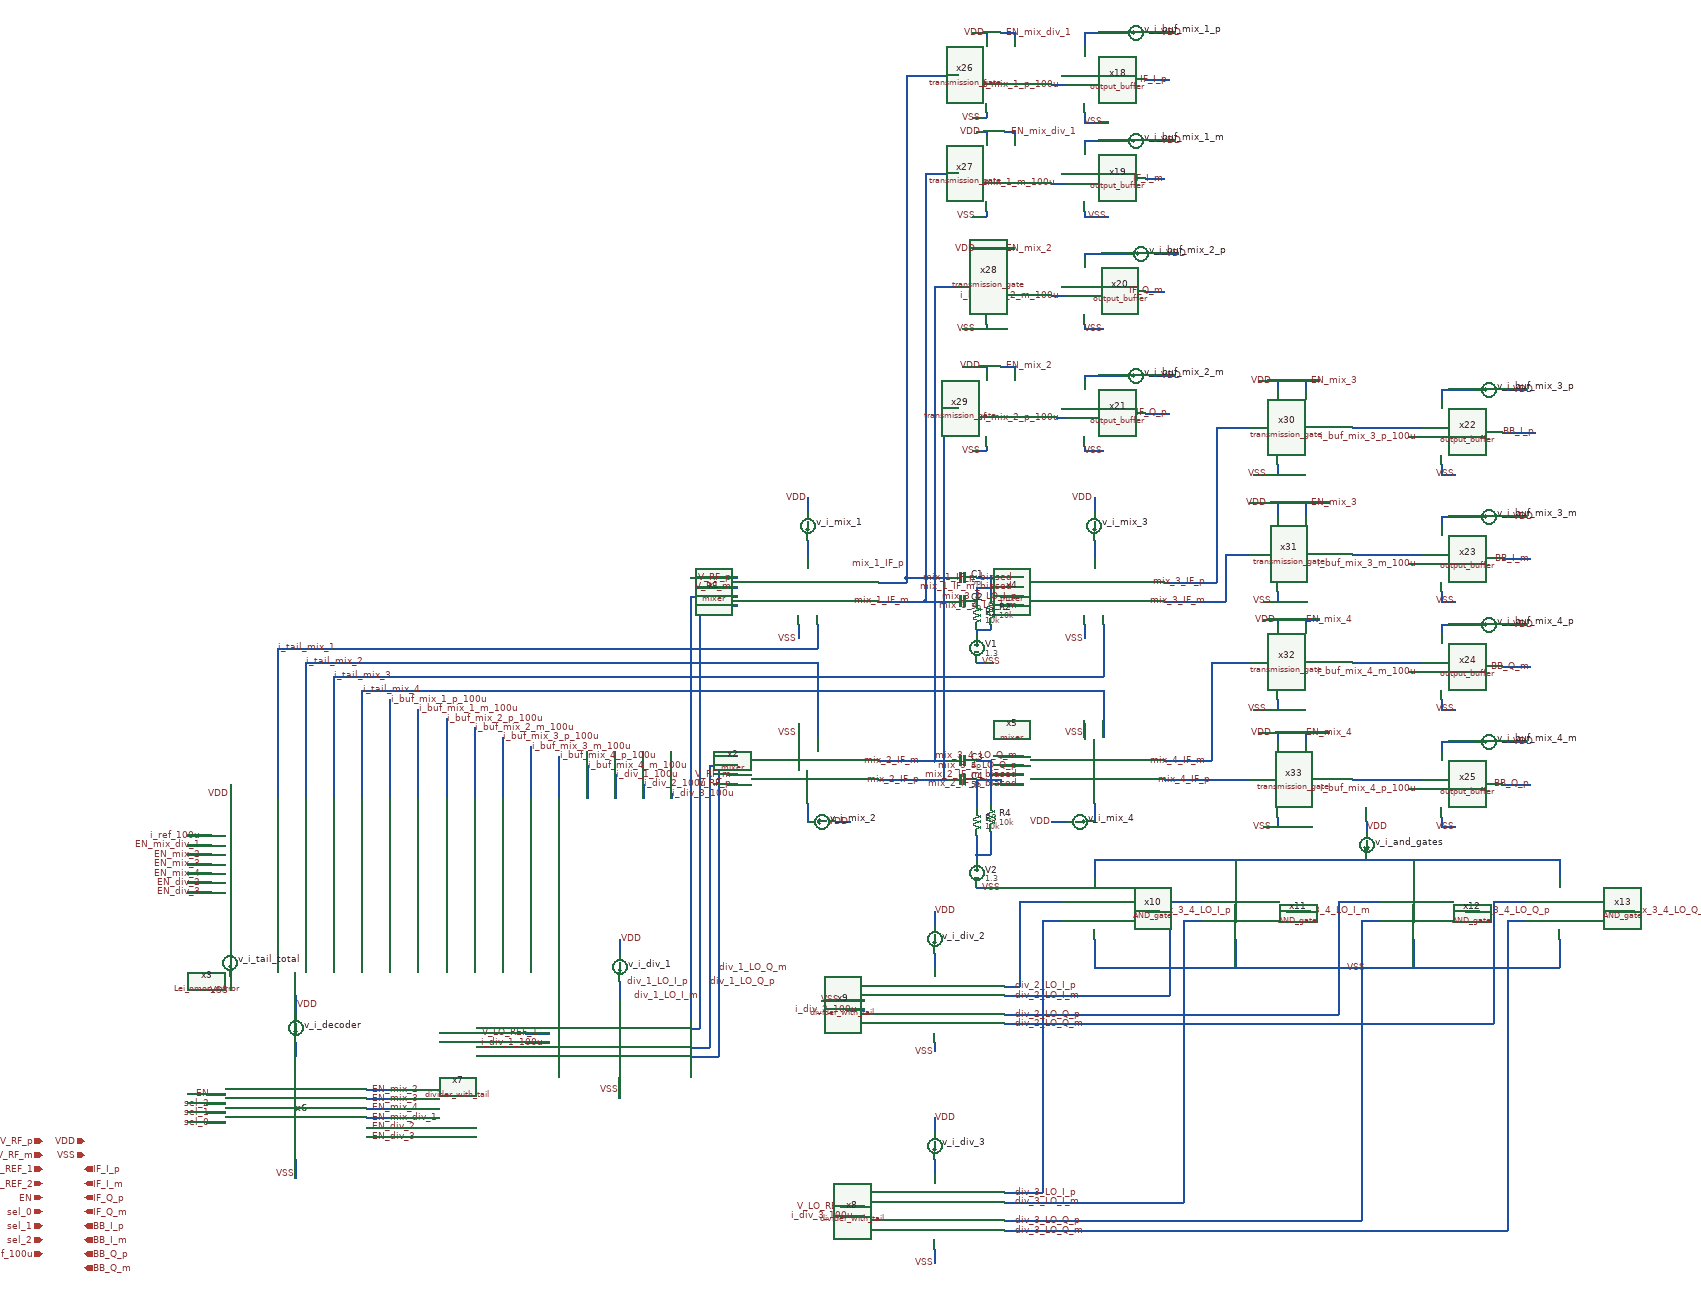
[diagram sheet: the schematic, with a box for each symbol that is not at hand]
v {xschem version=3.4.8RC file_version=1.3}
G {}
K {}
V {}
S {}
F {}
E {}
P 4 1 2100 -1410 {}
N 1630 -1150 1630 -1110 {lab=#net1}
N 1630 -1710 1630 -1670 {lab=#net2}
N 1780 -1620 1840 -1620 {lab=mix_1_IF_p}
N 1780 -1580 1840 -1580 {lab=mix_1_IF_m}
N 1780 -1200 1840 -1200 {lab=mix_2_IF_p}
N 1780 -1240 1840 -1240 {lab=mix_2_IF_m}
N 1610 -1320 1610 -1290 {lab=VSS}
N 2240 -1150 2240 -1110 {lab=#net3}
N 2240 -1710 2240 -1670 {lab=#net4}
N 2390 -1620 2450 -1620 {lab=mix_3_IF_p}
N 2390 -1580 2450 -1580 {lab=mix_3_IF_m}
N 2390 -1200 2450 -1200 {lab=mix_4_IF_p}
N 2390 -1240 2450 -1240 {lab=mix_4_IF_m}
N 2490 -1290 2490 -1240 {lab=mix_4_IF_m}
N 2220 -1320 2220 -1290 {lab=VSS}
N 500 -1480 500 -1350 {lab=i_tail_mix_1}
N 1040 -1480 1650 -1480 {lab=i_tail_mix_1}
N 1650 -1530 1650 -1480 {lab=i_tail_mix_1}
N 560 -1390 560 -1350 {lab=i_tail_mix_2}
N 1100 -1450 1650 -1450 {lab=i_tail_mix_2}
N 560 -1450 560 -1390 {lab=i_tail_mix_2}
N 1650 -1450 1650 -1440 {lab=i_tail_mix_2}
N 620 -1420 620 -1350 {lab=i_tail_mix_3}
N 1160 -1420 2260 -1420 {lab=i_tail_mix_3}
N 2260 -1530 2260 -1420 {lab=i_tail_mix_3}
N 680 -1390 680 -1350 {lab=i_tail_mix_4}
N 1220 -1390 2260 -1390 {lab=i_tail_mix_4}
N 2260 -1390 2260 -1290 {lab=i_tail_mix_4}
N 1610 -1530 1610 -1510 {lab=VSS}
N 1650 -1440 1650 -1290 {lab=i_tail_mix_2}
N 1380 -1440 1380 -690 {lab=div_1_LO_I_p}
N 1380 -1590 1480 -1590 {lab=div_1_LO_I_p}
N 1380 -670 1400 -670 {lab=div_1_LO_I_m}
N 1400 -1570 1480 -1570 {lab=div_1_LO_I_m}
N 1030 -640 1080 -640 {lab=i_div_1_100u}
N 1030 -660 1080 -660 {lab=V_LO_REF_1}
N 1700 -270 1750 -270 {lab=i_div_3_100u}
N 1700 -290 1750 -290 {lab=V_LO_REF_2}
N 1710 -710 1750 -710 {lab=i_div_2_100u}
N 1710 -730 1750 -730 {lab=VSS}
N 1900 -830 1900 -800 {lab=#net5}
N 1900 -640 1900 -620 {lab=VSS}
N 1900 -390 1900 -360 {lab=#net6}
N 1900 -200 1900 -170 {lab=VSS}
N 1380 -630 1420 -630 {lab=div_1_LO_Q_p}
N 1420 -1100 1420 -630 {lab=div_1_LO_Q_p}
N 1380 -610 1440 -610 {lab=div_1_LO_Q_m}
N 1440 -1080 1440 -610 {lab=div_1_LO_Q_m}
N 2050 -760 2070 -760 {lab=div_2_LO_I_p}
N 2050 -740 2080 -740 {lab=div_2_LO_I_m}
N 1660 -730 1710 -730 {lab=VSS}
N 2400 -920 2400 -740 {lab=div_2_LO_I_m}
N 2350 -920 2380 -920 {lab=mix_3_4_LO_I_p}
N 2650 -920 2700 -920 {lab=mix_3_4_LO_I_m}
N 2760 -920 2760 -760 {lab=div_2_LO_Q_p}
N 3090 -920 3090 -740 {lab=div_2_LO_Q_m}
N 3030 -920 3060 -920 {lab=mix_3_4_LO_Q_p}
N 3340 -920 3390 -920 {lab=mix_3_4_LO_Q_m}
N 2050 -700 2760 -700 {lab=div_2_LO_Q_p}
N 2760 -760 2760 -700 {lab=div_2_LO_Q_p}
N 3090 -740 3090 -690 {lab=div_2_LO_Q_m}
N 2240 -1030 2240 -1010 {lab=#net7}
N 3230 -1030 3230 -1010 {lab=#net7}
N 2540 -1030 2540 -990 {lab=#net7}
N 2920 -1030 2920 -990 {lab=#net7}
N 2240 -830 2240 -800 {lab=VSS}
N 3230 -820 3230 -800 {lab=VSS}
N 3230 -830 3230 -820 {lab=VSS}
N 2920 -830 2920 -800 {lab=VSS}
N 2540 -830 2540 -800 {lab=VSS}
N 2810 -900 2850 -900 {lab=div_3_LO_Q_p}
N 2050 -680 3090 -680 {lab=div_2_LO_Q_m}
N 3090 -690 3090 -680 {lab=div_2_LO_Q_m}
N 3120 -900 3160 -900 {lab=div_3_LO_Q_m}
N 2080 -740 2400 -740 {lab=div_2_LO_I_m}
N 2430 -900 2470 -900 {lab=div_3_LO_I_m}
N 2130 -900 2170 -900 {lab=div_3_LO_I_p}
N 1230 -770 1230 -730 {lab=#net8}
N 1230 -570 1230 -520 {lab=VSS}
N 690 -540 740 -540 {lab=EN_mix_2}
N 690 -520 740 -520 {lab=EN_mix_3}
N 690 -500 740 -500 {lab=EN_mix_4}
N 690 -480 740 -480 {lab=EN_mix_div_1}
N 690 -460 740 -460 {lab=EN_div_2}
N 690 -440 740 -440 {lab=EN_div_3}
N 350 -530 390 -530 {lab=EN}
N 350 -510 390 -510 {lab=sel_2}
N 350 -490 390 -490 {lab=sel_1}
N 350 -470 390 -470 {lab=sel_0}
N 540 -640 540 -610 {lab=#net9}
N 540 -390 540 -350 {lab=VSS}
N 1380 -1630 1480 -1630 {lab=V_RF_p}
N 1390 -1610 1480 -1610 {lab=V_RF_m}
N 1460 -1210 1480 -1210 {lab=V_RF_m}
N 1460 -1190 1480 -1190 {lab=V_RF_p}
N 2050 -320 2070 -320 {lab=div_3_LO_I_p}
N 2050 -300 2080 -300 {lab=div_3_LO_I_m}
N 1840 -1630 1840 -1620 {lab=mix_1_IF_p}
N 1840 -1580 1860 -1580 {lab=mix_1_IF_m}
N 1860 -1580 1880 -1580 {lab=mix_1_IF_m}
N 1880 -1690 1880 -1580 {lab=mix_1_IF_m}
N 2040 -1590 2090 -1590 {lab=mix_3_4_LO_I_p}
N 2040 -1570 2090 -1570 {lab=mix_3_4_LO_I_m}
N 1840 -1790 1840 -1630 {lab=mix_1_IF_p}
N 2220 -1530 2220 -1500 {lab=VSS}
N 1610 -1510 1610 -1500 {lab=VSS}
N 1840 -1240 1900 -1240 {lab=mix_2_IF_m}
N 1840 -1200 1920 -1200 {lab=mix_2_IF_p}
N 1920 -1230 1920 -1200 {lab=mix_2_IF_p}
N 1920 -1770 1920 -1230 {lab=mix_2_IF_p}
N 1880 -1870 1880 -1690 {lab=mix_1_IF_m}
N 1840 -2550 1840 -1790 {lab=mix_1_IF_p}
N 1840 -2700 1950 -2700 {lab=mix_1_IF_p}
N 1880 -2360 1880 -1870 {lab=mix_1_IF_m}
N 1880 -2490 1950 -2490 {lab=mix_1_IF_m}
N 1900 -2180 1900 -1810 {lab=mix_2_IF_m}
N 1900 -2250 1950 -2250 {lab=mix_2_IF_m}
N 1920 -1990 1920 -1770 {lab=mix_2_IF_p}
N 1920 -1990 1950 -1990 {lab=mix_2_IF_p}
N 2350 -2690 2400 -2690 {lab=IF_I_p}
N 2220 -2790 2220 -2760 {lab=#net10}
N 2220 -2790 2260 -2790 {lab=#net10}
N 2220 -2620 2220 -2600 {lab=VSS}
N 2220 -2600 2270 -2600 {lab=VSS}
N 2220 -2560 2220 -2550 {lab=#net11}
N 2220 -2560 2260 -2560 {lab=#net11}
N 2220 -2410 2220 -2400 {lab=VSS}
N 2220 -2400 2270 -2400 {lab=VSS}
N 2220 -2320 2220 -2310 {lab=#net12}
N 2220 -2320 2270 -2320 {lab=#net12}
N 2220 -2170 2220 -2160 {lab=VSS}
N 2220 -2160 2260 -2160 {lab=VSS}
N 2220 -2060 2220 -2050 {lab=#net13}
N 2220 -2060 2260 -2060 {lab=#net13}
N 2220 -1910 2220 -1900 {lab=VSS}
N 2220 -1900 2260 -1900 {lab=VSS}
N 2350 -1980 2400 -1980 {lab=IF_Q_p}
N 2350 -2240 2390 -2240 {lab=IF_Q_m}
N 2350 -2480 2390 -2480 {lab=IF_I_m}
N 2150 -2470 2180 -2470 {lab=i_buf_mix_1_m_100u}
N 2150 -2680 2180 -2680 {lab=i_buf_mix_1_p_100u}
N 2150 -2230 2180 -2230 {lab=i_buf_mix_2_m_100u}
N 2160 -1970 2180 -1970 {lab=i_buf_mix_2_p_100u}
N 2810 -1200 2930 -1200 {lab=#net14}
N 2930 -1200 2940 -1200 {lab=#net14}
N 2450 -1240 2490 -1240 {lab=mix_4_IF_m}
N 2490 -1390 2490 -1290 {lab=mix_4_IF_m}
N 2850 -1450 2940 -1450 {lab=#net15}
N 2810 -1680 2940 -1680 {lab=#net16}
N 2450 -1620 2500 -1620 {lab=mix_3_IF_p}
N 2500 -1770 2500 -1620 {lab=mix_3_IF_p}
N 2860 -1950 2940 -1950 {lab=#net17}
N 2980 -2030 2980 -2010 {lab=#net18}
N 2980 -2030 3010 -2030 {lab=#net18}
N 2980 -1870 2980 -1850 {lab=VSS}
N 2980 -1850 3010 -1850 {lab=VSS}
N 2980 -1760 2980 -1740 {lab=#net19}
N 2980 -1760 3010 -1760 {lab=#net19}
N 2980 -1600 2980 -1580 {lab=VSS}
N 2980 -1580 3010 -1580 {lab=VSS}
N 2980 -1530 2980 -1510 {lab=#net20}
N 2980 -1530 3010 -1530 {lab=#net20}
N 2980 -1370 2980 -1350 {lab=VSS}
N 2980 -1350 3010 -1350 {lab=VSS}
N 2980 -1280 2980 -1260 {lab=#net21}
N 2980 -1280 3010 -1280 {lab=#net21}
N 2980 -1120 2980 -1100 {lab=VSS}
N 2980 -1100 3010 -1100 {lab=VSS}
N 2910 -1930 2940 -1930 {lab=i_buf_mix_3_p_100u}
N 2910 -1660 2940 -1660 {lab=i_buf_mix_3_m_100u}
N 2910 -1430 2940 -1430 {lab=i_buf_mix_4_m_100u}
N 2910 -1180 2940 -1180 {lab=i_buf_mix_4_p_100u}
N 3110 -1940 3180 -1940 {lab=BB_I_p}
N 3110 -1670 3170 -1670 {lab=BB_I_m}
N 3110 -1440 3170 -1440 {lab=BB_Q_m}
N 3110 -1190 3170 -1190 {lab=BB_Q_p}
N 640 -1480 1040 -1480 {lab=i_tail_mix_1}
N 700 -1450 1100 -1450 {lab=i_tail_mix_2}
N 760 -1420 1160 -1420 {lab=i_tail_mix_3}
N 820 -1390 1220 -1390 {lab=i_tail_mix_4}
N 2040 -1250 2090 -1250 {lab=mix_3_4_LO_Q_m}
N 2040 -1230 2090 -1230 {lab=mix_3_4_LO_Q_p}
N 2040 -1210 2090 -1210 {lab=mix_2_IF_m_biased}
N 2040 -1190 2090 -1190 {lab=mix_2_IF_p_biased}
N 500 -1350 500 -1240 {lab=i_tail_mix_1}
N 560 -1350 560 -1240 {lab=i_tail_mix_2}
N 620 -1340 620 -1240 {lab=i_tail_mix_3}
N 620 -1350 620 -1340 {lab=i_tail_mix_3}
N 680 -1350 680 -1240 {lab=i_tail_mix_4}
N 740 -1370 740 -1240 {lab=i_buf_mix_1_p_100u}
N 800 -1350 800 -1240 {lab=i_buf_mix_1_m_100u}
N 860 -1330 860 -1240 {lab=i_buf_mix_2_p_100u}
N 920 -1300 920 -1240 {lab=i_buf_mix_2_m_100u}
N 920 -1310 920 -1300 {lab=i_buf_mix_2_m_100u}
N 500 -1480 640 -1480 {lab=i_tail_mix_1}
N 560 -1450 700 -1450 {lab=i_tail_mix_2}
N 620 -1420 760 -1420 {lab=i_tail_mix_3}
N 680 -1390 820 -1390 {lab=i_tail_mix_4}
N 500 -1240 500 -1230 {lab=i_tail_mix_1}
N 560 -1240 560 -1230 {lab=i_tail_mix_2}
N 620 -1240 620 -1230 {lab=i_tail_mix_3}
N 680 -1240 680 -1230 {lab=i_tail_mix_4}
N 740 -1240 740 -1230 {lab=i_buf_mix_1_p_100u}
N 800 -1240 800 -1230 {lab=i_buf_mix_1_m_100u}
N 860 -1240 860 -1230 {lab=i_buf_mix_2_p_100u}
N 920 -1240 920 -1230 {lab=i_buf_mix_2_m_100u}
N 980 -1240 980 -1230 {lab=i_buf_mix_3_p_100u}
N 1040 -1240 1040 -1230 {lab=i_buf_mix_3_m_100u}
N 980 -1290 980 -1240 {lab=i_buf_mix_3_p_100u}
N 1040 -1270 1040 -1240 {lab=i_buf_mix_3_m_100u}
N 1100 -1250 1100 -1230 {lab=i_buf_mix_4_p_100u}
N 1900 -1810 1900 -1240 {lab=mix_2_IF_m}
N 310 -1080 360 -1080 {lab=i_ref_100u}
N 310 -1060 360 -1060 {lab=EN_mix_div_1}
N 310 -1040 360 -1040 {lab=EN_mix_2}
N 310 -1020 360 -1020 {lab=EN_mix_3}
N 310 -1000 360 -1000 {lab=EN_mix_4}
N 400 -1190 400 -1160 {lab=VDD}
N 400 -870 400 -840 {lab=#net22}
N 1630 -1800 1630 -1770 {lab=VDD}
N 2240 -1800 2240 -1770 {lab=VDD}
N 2150 -1110 2180 -1110 {lab=VDD}
N 1690 -1110 1720 -1110 {lab=VDD}
N 1230 -860 1230 -830 {lab=VDD}
N 1900 -920 1900 -890 {lab=VDD}
N 1900 -480 1900 -450 {lab=VDD}
N 400 -780 400 -750 {lab=VSS}
N 2360 -2790 2410 -2790 {lab=VDD}
N 2260 -2790 2300 -2790 {lab=#net10}
N 2360 -2560 2410 -2560 {lab=VDD}
N 2260 -2560 2300 -2560 {lab=#net11}
N 2370 -2320 2420 -2320 {lab=VDD}
N 2270 -2320 2310 -2320 {lab=#net12}
N 2360 -2060 2410 -2060 {lab=VDD}
N 2260 -2060 2300 -2060 {lab=#net13}
N 3110 -2030 3160 -2030 {lab=VDD}
N 3010 -2030 3050 -2030 {lab=#net18}
N 3110 -1760 3160 -1760 {lab=VDD}
N 3010 -1760 3050 -1760 {lab=#net19}
N 3110 -1530 3160 -1530 {lab=VDD}
N 3010 -1530 3050 -1530 {lab=#net20}
N 3110 -1280 3160 -1280 {lab=VDD}
N 3010 -1280 3050 -1280 {lab=#net21}
N 540 -740 540 -700 {lab=VDD}
N 2820 -1110 2820 -1090 {lab=VDD}
N 2170 -1990 2180 -1990 {lab=#net23}
N 2170 -2250 2180 -2250 {lab=#net24}
N 2170 -2490 2180 -2490 {lab=#net25}
N 2170 -2700 2180 -2700 {lab=#net26}
N 2010 -2170 2010 -2160 {lab=VSS}
N 1960 -2160 2010 -2160 {lab=VSS}
N 2010 -2080 2010 -2070 {lab=VDD}
N 1960 -2080 2010 -2080 {lab=VDD}
N 2010 -1910 2010 -1900 {lab=VSS}
N 1980 -1900 2010 -1900 {lab=VSS}
N 1980 -2330 2010 -2330 {lab=VDD}
N 1840 -2700 1840 -2550 {lab=mix_1_IF_p}
N 2010 -2620 2010 -2610 {lab=VSS}
N 1980 -2610 2010 -2610 {lab=VSS}
N 2010 -2790 2010 -2780 {lab=VDD}
N 1980 -2790 2010 -2790 {lab=VDD}
N 2070 -2790 2070 -2780 {lab=EN_mix_div_1}
N 2040 -2790 2070 -2790 {lab=EN_mix_div_1}
N 1880 -2490 1880 -2360 {lab=mix_1_IF_m}
N 2010 -2410 2010 -2400 {lab=VSS}
N 1980 -2400 2010 -2400 {lab=VSS}
N 2010 -2580 2010 -2570 {lab=VDD}
N 1990 -2580 2010 -2580 {lab=VDD}
N 2070 -2580 2070 -2570 {lab=EN_mix_div_1}
N 2050 -2580 2070 -2580 {lab=EN_mix_div_1}
N 1900 -2240 1900 -2180 {lab=mix_2_IF_m}
N 1900 -2250 1900 -2240 {lab=mix_2_IF_m}
N 2070 -2080 2070 -2070 {lab=EN_mix_2}
N 2040 -2080 2070 -2080 {lab=EN_mix_2}
N 2050 -2330 2070 -2330 {lab=EN_mix_2}
N 2450 -1200 2570 -1200 {lab=mix_4_IF_p}
N 2790 -1200 2810 -1200 {lab=#net14}
N 2630 -1300 2630 -1280 {lab=VDD}
N 2590 -1300 2630 -1300 {lab=VDD}
N 2630 -1120 2630 -1100 {lab=VSS}
N 2600 -1100 2630 -1100 {lab=VSS}
N 2490 -1450 2490 -1390 {lab=mix_4_IF_m}
N 2490 -1450 2570 -1450 {lab=mix_4_IF_m}
N 2630 -1370 2630 -1350 {lab=VSS}
N 2580 -1350 2630 -1350 {lab=VSS}
N 2630 -1540 2630 -1530 {lab=VDD}
N 2600 -1540 2630 -1540 {lab=VDD}
N 2690 -1540 2690 -1530 {lab=EN_mix_4}
N 2690 -1540 2720 -1540 {lab=EN_mix_4}
N 2790 -1450 2850 -1450 {lab=#net15}
N 2450 -1580 2520 -1580 {lab=mix_3_IF_m}
N 2500 -1950 2500 -1770 {lab=mix_3_IF_p}
N 2500 -1950 2560 -1950 {lab=mix_3_IF_p}
N 2560 -1950 2570 -1950 {lab=mix_3_IF_p}
N 2520 -1680 2520 -1580 {lab=mix_3_IF_m}
N 2520 -1680 2570 -1680 {lab=mix_3_IF_m}
N 2630 -1790 2630 -1760 {lab=VDD}
N 2570 -1790 2630 -1790 {lab=VDD}
N 2690 -1790 2690 -1760 {lab=EN_mix_3}
N 2690 -1790 2740 -1790 {lab=EN_mix_3}
N 2630 -1600 2630 -1580 {lab=VSS}
N 2600 -1580 2630 -1580 {lab=VSS}
N 2630 -1870 2630 -1850 {lab=VSS}
N 2580 -1850 2630 -1850 {lab=VSS}
N 2630 -2050 2630 -2030 {lab=VDD}
N 2590 -2050 2630 -2050 {lab=VDD}
N 2690 -2050 2690 -2030 {lab=EN_mix_3}
N 2690 -2050 2720 -2050 {lab=EN_mix_3}
N 2790 -1950 2860 -1950 {lab=#net17}
N 2690 -1300 2690 -1280 {lab=EN_mix_4}
N 2690 -1300 2740 -1300 {lab=EN_mix_4}
N 2790 -1680 2810 -1680 {lab=#net16}
N 1840 -1630 1930 -1630 {lab=mix_1_IF_p}
N 1880 -1580 1930 -1580 {lab=mix_1_IF_m}
N 1990 -1610 1990 -1580 {lab=mix_1_IF_m_biased}
N 1990 -1520 1990 -1510 {lab=#net27}
N 1990 -1520 2020 -1520 {lab=#net27}
N 1990 -1040 1990 -1030 {lab=#net28}
N 1990 -1040 2020 -1040 {lab=#net28}
N 2020 -1070 2020 -1040 {lab=#net28}
N 1920 -1200 1930 -1200 {lab=mix_2_IF_p}
N 1900 -1240 1930 -1240 {lab=mix_2_IF_m}
N 1990 -1240 2020 -1240 {lab=mix_2_IF_m_biased}
N 2020 -1240 2020 -1210 {lab=mix_2_IF_m_biased}
N 1990 -1200 1990 -1190 {lab=mix_2_IF_p_biased}
N 1990 -1450 2010 -1450 {lab=VSS}
N 1990 -970 2010 -970 {lab=VSS}
N 2020 -1530 2020 -1520 {lab=#net27}
N 1990 -1080 1990 -1040 {lab=#net28}
N 2020 -1090 2020 -1070 {lab=#net28}
N 2020 -1210 2020 -1150 {lab=mix_2_IF_m_biased}
N 1990 -1190 1990 -1140 {lab=mix_2_IF_p_biased}
N 1380 -1590 1380 -1440 {lab=div_1_LO_I_p
}
N 310 -980 360 -980 {lab=EN_div_2}
N 310 -960 360 -960 {lab=EN_div_3}
N 500 -1230 500 -1160 {lab=i_tail_mix_1}
N 560 -1230 560 -1160 {lab=i_tail_mix_2}
N 620 -1230 620 -1160 {lab=i_tail_mix_3}
N 680 -1230 680 -1160 {lab=i_tail_mix_4}
N 740 -1230 740 -1170 {lab=i_buf_mix_1_p_100u}
N 740 -1170 740 -1160 {lab=i_buf_mix_1_p_100u}
N 800 -1230 800 -1160 {lab=i_buf_mix_1_m_100u}
N 860 -1230 860 -1160 {lab=i_buf_mix_2_p_100u}
N 920 -1230 920 -1160 {lab=i_buf_mix_2_m_100u}
N 980 -1230 980 -1160 {lab=i_buf_mix_3_p_100u}
N 1040 -1230 1040 -1160 {lab=i_buf_mix_3_m_100u}
N 1100 -1230 1100 -1160 {lab=i_buf_mix_4_p_100u}
N 1160 -1230 1160 -1160 {lab=i_buf_mix_4_m_100u}
N 1220 -1210 1220 -1160 {lab=i_div_1_100u}
N 1280 -1190 1280 -1160 {lab=i_div_2_100u}
N 1340 -1170 1340 -1160 {lab=i_div_3_100u}
N 1440 -1250 1480 -1250 {lab=div_1_LO_Q_m}
N 1420 -1230 1420 -1100 {lab=div_1_LO_Q_p
spice_ignore=short}
N 1420 -1230 1480 -1230 {lab=div_1_LO_Q_p}
N 1440 -1250 1440 -1080 {lab=div_1_LO_Q_m
spice_ignore=short}
N 1990 -1630 2020 -1630 {lab=mix_1_IF_p_biased}
N 1990 -1610 2010 -1610 {lab=mix_1_IF_m_biased}
N 2020 -1620 2020 -1590 {lab=mix_1_IF_p_biased}
N 2020 -1630 2020 -1620 {lab=mix_1_IF_p_biased}
N 2010 -1610 2090 -1610 {lab=mix_1_IF_m_biased}
N 2020 -1630 2090 -1630 {lab=mix_1_IF_p_biased}
N 2040 -1200 2040 -1190 {lab=mix_2_IF_p_biased}
N 1990 -1200 2040 -1200 {lab=mix_2_IF_p_biased}
N 2020 -1210 2040 -1210 {lab=mix_2_IF_m_biased}
N 1400 -1350 1400 -670 {lab=div_1_LO_I_m}
N 1400 -1570 1400 -1350 {lab=div_1_LO_I_m
}
N 2240 -1010 2240 -990 {lab=#net7}
N 2240 -850 2240 -830 {lab=VSS}
N 2240 -860 2240 -850 {lab=VSS}
N 2540 -860 2540 -830 {lab=VSS}
N 2920 -850 2920 -830 {lab=VSS}
N 2920 -860 2920 -850 {lab=VSS}
N 2240 -1030 3230 -1030 {lab=#net7}
N 2240 -800 3230 -800 {lab=VSS}
N 2140 -940 2170 -940 {lab=div_2_LO_I_p}
N 2400 -940 2400 -920 {lab=div_2_LO_I_m}
N 2400 -940 2470 -940 {lab=div_2_LO_I_m}
N 3090 -940 3090 -920 {lab=div_2_LO_Q_m}
N 3090 -940 3160 -940 {lab=div_2_LO_Q_m}
N 2760 -940 2760 -920 {lab=div_2_LO_Q_p}
N 2760 -940 2850 -940 {lab=div_2_LO_Q_p}
N 3230 -860 3230 -830 {lab=VSS}
N 3230 -1010 3230 -990 {lab=#net7}
N 2080 -300 2220 -300 {lab=div_3_LO_I_m}
N 2050 -260 2220 -260 {lab=div_3_LO_Q_p}
N 2050 -240 2220 -240 {lab=div_3_LO_Q_m}
N 2070 -760 2080 -760 {lab=div_2_LO_I_p}
N 2080 -940 2080 -760 {lab=div_2_LO_I_p}
N 2080 -940 2140 -940 {lab=div_2_LO_I_p}
N 2130 -900 2130 -320 {lab=div_3_LO_I_p}
N 2070 -320 2130 -320 {lab=div_3_LO_I_p}
N 2430 -900 2430 -300 {lab=div_3_LO_I_m}
N 2230 -300 2430 -300 {lab=div_3_LO_I_m}
N 2220 -300 2230 -300 {lab=div_3_LO_I_m}
N 2220 -260 2760 -260 {lab=div_3_LO_Q_p}
N 2810 -900 2810 -260 {lab=div_3_LO_Q_p}
N 2760 -260 2810 -260 {lab=div_3_LO_Q_p}
N 3120 -900 3120 -240 {lab=div_3_LO_Q_m}
N 2220 -240 3120 -240 {lab=div_3_LO_Q_m}
C {title.sym} 160 -30 0 0 {name=l1 author="Lei Chen"}
C {mixer/schematic/mixer.sym} 1630 -1600 0 0 {name=x1
}
C {mixer/schematic/mixer.sym} 1630 -1220 2 1 {name=x2
}
C {mixer/schematic/mixer.sym} 2240 -1600 0 0 {name=x4
}
C {mixer/schematic/mixer.sym} 2240 -1220 2 1 {name=x5
}
C {decoder/schematic/decoder.sym} 540 -500 0 0 {name=x6}
C {iopin.sym} 90 -430 0 0 {name=p1 lab=VDD}
C {iopin.sym} 90 -400 0 0 {name=p2 lab=VSS}
C {lab_wire.sym} 2820 -1100 0 1 {name=p3 sig_type=std_logic lab=VDD}
C {lab_wire.sym} 2820 -800 0 0 {name=p4 sig_type=std_logic lab=VSS}
C {lab_wire.sym} 1900 -620 0 0 {name=p6 sig_type=std_logic lab=VSS}
C {lab_wire.sym} 1900 -170 0 0 {name=p8 sig_type=std_logic lab=VSS}
C {ipin.sym} 0 -430 0 0 {name=p9 lab=V_RF_p}
C {ipin.sym} 0 -400 0 0 {name=p10 lab=V_RF_m}
C {ipin.sym} 0 -370 0 0 {name=p11 lab=V_LO_REF_1}
C {ipin.sym} 0 -340 0 0 {name=p12 lab=V_LO_REF_2}
C {ipin.sym} 0 -310 0 0 {name=p13 lab=EN}
C {ipin.sym} 0 -280 0 0 {name=p14 lab=sel_0}
C {ipin.sym} 0 -250 0 0 {name=p15 lab=sel_1}
C {ipin.sym} 0 -220 0 0 {name=p16 lab=sel_2}
C {lab_wire.sym} 360 -530 0 0 {name=p17 sig_type=std_logic lab=EN}
C {lab_wire.sym} 360 -510 0 0 {name=p18 sig_type=std_logic lab=sel_2}
C {lab_wire.sym} 360 -490 0 0 {name=p19 sig_type=std_logic lab=sel_1}
C {lab_wire.sym} 360 -470 0 0 {name=p20 sig_type=std_logic lab=sel_0}
C {lab_wire.sym} 700 -540 0 1 {name=p21 sig_type=std_logic lab=EN_mix_2}
C {lab_wire.sym} 700 -520 0 1 {name=p22 sig_type=std_logic lab=EN_mix_3}
C {lab_wire.sym} 700 -500 0 1 {name=p23 sig_type=std_logic lab=EN_mix_4}
C {lab_wire.sym} 700 -480 0 1 {name=p24 sig_type=std_logic lab=EN_mix_div_1}
C {lab_wire.sym} 700 -460 0 1 {name=p25 sig_type=std_logic lab=EN_div_2}
C {lab_wire.sym} 700 -440 0 1 {name=p26 sig_type=std_logic lab=EN_div_3}
C {lab_wire.sym} 340 -1020 0 0 {name=p27 sig_type=std_logic lab=EN_mix_3}
C {lab_wire.sym} 340 -1040 0 0 {name=p28 sig_type=std_logic lab=EN_mix_2}
C {lab_wire.sym} 340 -1000 0 0 {name=p29 sig_type=std_logic lab=EN_mix_4}
C {lab_wire.sym} 340 -1060 0 0 {name=p30 sig_type=std_logic lab=EN_mix_div_1}
C {ipin.sym} 0 -190 0 0 {name=p31 lab=i_ref_100u}
C {lab_wire.sym} 340 -1080 0 0 {name=p32 sig_type=std_logic lab=i_ref_100u}
C {lab_wire.sym} 540 -720 0 1 {name=p36 sig_type=std_logic lab=VDD}
C {lab_wire.sym} 1230 -540 0 0 {name=p37 sig_type=std_logic lab=VSS}
C {lab_wire.sym} 540 -360 0 0 {name=p38 sig_type=std_logic lab=VSS}
C {lab_wire.sym} 500 -1480 0 1 {name=p39 sig_type=std_logic lab=i_tail_mix_1}
C {lab_wire.sym} 560 -1450 0 1 {name=p40 sig_type=std_logic lab=i_tail_mix_2}
C {lab_wire.sym} 620 -1420 0 1 {name=p41 sig_type=std_logic lab=i_tail_mix_3}
C {lab_wire.sym} 680 -1390 0 1 {name=p42 sig_type=std_logic lab=i_tail_mix_4}
C {lab_wire.sym} 1470 -1630 0 0 {name=p43 sig_type=std_logic lab=V_RF_p}
C {lab_wire.sym} 1470 -1610 0 0 {name=p44 sig_type=std_logic lab=V_RF_m}
C {lab_wire.sym} 1470 -1190 0 0 {name=p45 sig_type=std_logic lab=V_RF_p}
C {lab_wire.sym} 1470 -1210 0 0 {name=p46 sig_type=std_logic lab=V_RF_m}
C {lab_wire.sym} 1380 -770 0 0 {name=p47 sig_type=std_logic lab=div_1_LO_I_p}
C {lab_wire.sym} 1400 -740 0 0 {name=p48 sig_type=std_logic lab=div_1_LO_I_m}
C {lab_wire.sym} 1440 -800 0 1 {name=p49 sig_type=std_logic lab=div_1_LO_Q_m}
C {lab_wire.sym} 1420 -770 0 1 {name=p50 sig_type=std_logic lab=div_1_LO_Q_p}
C {lab_wire.sym} 1060 -660 0 0 {name=p51 sig_type=std_logic lab=V_LO_REF_1}
C {lab_wire.sym} 1730 -290 0 0 {name=p55 sig_type=std_logic lab=V_LO_REF_2}
C {lab_wire.sym} 2070 -760 0 1 {name=p56 sig_type=std_logic lab=div_2_LO_I_p}
C {lab_wire.sym} 2070 -740 0 1 {name=p57 sig_type=std_logic lab=div_2_LO_I_m}
C {lab_wire.sym} 2070 -700 0 1 {name=p58 sig_type=std_logic lab=div_2_LO_Q_p}
C {lab_wire.sym} 2070 -680 0 1 {name=p59 sig_type=std_logic lab=div_2_LO_Q_m}
C {lab_wire.sym} 2070 -320 0 1 {name=p62 sig_type=std_logic lab=div_3_LO_I_p}
C {lab_wire.sym} 2070 -300 0 1 {name=p63 sig_type=std_logic lab=div_3_LO_I_m}
C {lab_wire.sym} 2070 -260 0 1 {name=p64 sig_type=std_logic lab=div_3_LO_Q_p}
C {lab_wire.sym} 2070 -240 0 1 {name=p65 sig_type=std_logic lab=div_3_LO_Q_m}
C {lab_wire.sym} 2370 -920 0 1 {name=p70 sig_type=std_logic lab=mix_3_4_LO_I_p}
C {lab_wire.sym} 2660 -920 0 1 {name=p71 sig_type=std_logic lab=mix_3_4_LO_I_m}
C {lab_wire.sym} 3040 -920 0 1 {name=p72 sig_type=std_logic lab=mix_3_4_LO_Q_p}
C {lab_wire.sym} 3380 -920 0 1 {name=p73 sig_type=std_logic lab=mix_3_4_LO_Q_m}
C {lab_wire.sym} 2220 -1300 0 0 {name=p84 sig_type=std_logic lab=VSS}
C {lab_wire.sym} 1610 -1300 0 0 {name=p85 sig_type=std_logic lab=VSS}
C {lab_wire.sym} 1610 -1500 0 0 {name=p86 sig_type=std_logic lab=VSS}
C {lab_wire.sym} 2220 -1500 0 0 {name=p87 sig_type=std_logic lab=VSS}
C {lab_wire.sym} 1630 -1800 0 0 {name=p89 sig_type=std_logic lab=VDD}
C {output_buffer/schematic/output_buffer.sym} 2260 -2690 0 0 {name=x18}
C {output_buffer/schematic/output_buffer.sym} 2260 -2480 0 0 {name=x19}
C {output_buffer/schematic/output_buffer.sym} 2260 -2240 0 0 {name=x20}
C {output_buffer/schematic/output_buffer.sym} 2260 -1980 0 0 {name=x21}
C {output_buffer/schematic/output_buffer.sym} 3020 -1940 0 0 {name=x22}
C {output_buffer/schematic/output_buffer.sym} 3020 -1670 0 0 {name=x23}
C {output_buffer/schematic/output_buffer.sym} 3020 -1440 0 0 {name=x24}
C {output_buffer/schematic/output_buffer.sym} 3020 -1190 0 0 {name=x25}
C {lab_wire.sym} 1840 -1660 0 0 {name=p90 sig_type=std_logic lab=mix_1_IF_p}
C {lab_wire.sym} 1850 -1580 0 0 {name=p91 sig_type=std_logic lab=mix_1_IF_m}
C {lab_wire.sym} 1870 -1200 0 0 {name=p92 sig_type=std_logic lab=mix_2_IF_p}
C {lab_wire.sym} 1870 -1240 0 0 {name=p93 sig_type=std_logic lab=mix_2_IF_m}
C {lab_wire.sym} 2490 -1200 0 0 {name=p94 sig_type=std_logic lab=mix_4_IF_p}
C {lab_wire.sym} 2480 -1240 0 0 {name=p95 sig_type=std_logic lab=mix_4_IF_m}
C {lab_wire.sym} 2480 -1620 0 0 {name=p96 sig_type=std_logic lab=mix_3_IF_p}
C {lab_wire.sym} 2480 -1580 0 0 {name=p97 sig_type=std_logic lab=mix_3_IF_m}
C {lab_wire.sym} 3010 -1850 0 0 {name=p99 sig_type=std_logic lab=VSS}
C {lab_wire.sym} 3010 -1580 0 0 {name=p101 sig_type=std_logic lab=VSS}
C {lab_wire.sym} 3010 -1350 0 0 {name=p103 sig_type=std_logic lab=VSS}
C {lab_wire.sym} 3010 -1100 0 0 {name=p105 sig_type=std_logic lab=VSS}
C {lab_wire.sym} 2260 -1900 0 0 {name=p107 sig_type=std_logic lab=VSS}
C {lab_wire.sym} 2260 -2160 0 0 {name=p108 sig_type=std_logic lab=VSS}
C {lab_wire.sym} 2270 -2400 0 0 {name=p110 sig_type=std_logic lab=VSS}
C {lab_wire.sym} 2260 -2600 0 0 {name=p111 sig_type=std_logic lab=VSS}
C {lab_wire.sym} 2380 -2790 0 1 {name=p113 sig_type=std_logic lab=VDD}
C {opin.sym} 90 -370 0 0 {name=p114 lab=IF_I_p}
C {opin.sym} 90 -340 0 0 {name=p115 lab=IF_I_m}
C {opin.sym} 90 -310 0 0 {name=p116 lab=IF_Q_p}
C {opin.sym} 90 -280 0 0 {name=p117 lab=IF_Q_m}
C {opin.sym} 90 -250 0 0 {name=p118 lab=BB_I_p}
C {opin.sym} 90 -220 0 0 {name=p119 lab=BB_I_m}
C {opin.sym} 90 -190 0 0 {name=p120 lab=BB_Q_p}
C {opin.sym} 90 -160 0 0 {name=p121 lab=BB_Q_m}
C {lab_wire.sym} 2400 -2690 0 0 {name=p122 sig_type=std_logic lab=IF_I_p}
C {lab_wire.sym} 2390 -2480 0 0 {name=p123 sig_type=std_logic lab=IF_I_m}
C {lab_wire.sym} 2400 -1980 0 0 {name=p124 sig_type=std_logic lab=IF_Q_p}
C {lab_wire.sym} 2390 -2240 0 0 {name=p125 sig_type=std_logic lab=IF_Q_m}
C {lab_wire.sym} 3180 -1940 0 0 {name=p126 sig_type=std_logic lab=BB_I_p}
C {lab_wire.sym} 3170 -1670 0 0 {name=p127 sig_type=std_logic lab=BB_I_m}
C {lab_wire.sym} 3170 -1190 0 0 {name=p128 sig_type=std_logic lab=BB_Q_p}
C {lab_wire.sym} 3170 -1440 0 0 {name=p129 sig_type=std_logic lab=BB_Q_m}
C {mirrors/schematic/Lei_nmos_mirror.sym} 530 -1020 0 0 {name=x3}
C {lab_wire.sym} 2080 -1590 0 0 {name=p130 sig_type=std_logic lab=mix_3_4_LO_I_p}
C {lab_wire.sym} 2080 -1570 0 0 {name=p131 sig_type=std_logic lab=mix_3_4_LO_I_m
value=1u}
C {lab_wire.sym} 740 -1370 0 1 {name=p134 sig_type=std_logic lab=i_buf_mix_1_p_100u}
C {lab_wire.sym} 800 -1350 0 1 {name=p135 sig_type=std_logic lab=i_buf_mix_1_m_100u}
C {lab_wire.sym} 860 -1330 0 1 {name=p136 sig_type=std_logic lab=i_buf_mix_2_p_100u}
C {lab_wire.sym} 920 -1310 0 1 {name=p137 sig_type=std_logic lab=i_buf_mix_2_m_100u}
C {lab_wire.sym} 980 -1290 0 1 {name=p138 sig_type=std_logic lab=i_buf_mix_3_p_100u}
C {lab_wire.sym} 1040 -1270 0 1 {name=p139 sig_type=std_logic lab=i_buf_mix_3_m_100u}
C {lab_wire.sym} 1100 -1250 0 1 {name=p140 sig_type=std_logic lab=i_buf_mix_4_p_100u}
C {lab_wire.sym} 1160 -1230 0 1 {name=p141 sig_type=std_logic lab=i_buf_mix_4_m_100u}
C {lab_wire.sym} 2170 -2680 0 0 {name=p142 sig_type=std_logic lab=i_buf_mix_1_p_100u}
C {lab_wire.sym} 2160 -2470 0 0 {name=p143 sig_type=std_logic lab=i_buf_mix_1_m_100u}
C {lab_wire.sym} 2170 -1970 0 0 {name=p144 sig_type=std_logic lab=i_buf_mix_2_p_100u}
C {lab_wire.sym} 2170 -2230 0 0 {name=p145 sig_type=std_logic lab=i_buf_mix_2_m_100u}
C {lab_wire.sym} 2930 -1930 0 0 {name=p146 sig_type=std_logic lab=i_buf_mix_3_p_100u}
C {lab_wire.sym} 2930 -1660 0 0 {name=p147 sig_type=std_logic lab=i_buf_mix_3_m_100u}
C {lab_wire.sym} 2930 -1180 0 0 {name=p148 sig_type=std_logic lab=i_buf_mix_4_p_100u}
C {lab_wire.sym} 2930 -1430 0 0 {name=p149 sig_type=std_logic lab=i_buf_mix_4_m_100u}
C {lab_wire.sym} 400 -1170 0 0 {name=p33 sig_type=std_logic lab=VDD}
C {lab_wire.sym} 400 -750 0 0 {name=p34 sig_type=std_logic lab=VSS}
C {ammeter.sym} 1630 -1740 0 0 {name=v_i_mix_1 savecurrent=true spice_ignore=0}
C {lab_wire.sym} 2240 -1800 0 0 {name=p88 sig_type=std_logic lab=VDD}
C {ammeter.sym} 2240 -1740 0 0 {name=v_i_mix_3 savecurrent=true spice_ignore=0}
C {lab_wire.sym} 2150 -1110 3 1 {name=p150 sig_type=std_logic lab=VDD}
C {ammeter.sym} 2210 -1110 3 1 {name=v_i_mix_4 savecurrent=true spice_ignore=0}
C {lab_wire.sym} 1720 -1110 1 0 {name=p83 sig_type=std_logic lab=VDD}
C {ammeter.sym} 1660 -1110 1 0 {name=v_i_mix_2 savecurrent=true spice_ignore=0}
C {lab_wire.sym} 1230 -860 0 1 {name=p35 sig_type=std_logic lab=VDD}
C {ammeter.sym} 1230 -800 0 0 {name=v_i_div_1 savecurrent=true spice_ignore=0}
C {lab_wire.sym} 1900 -920 0 1 {name=p82 sig_type=std_logic lab=VDD}
C {ammeter.sym} 1900 -860 0 0 {name=v_i_div_2 savecurrent=true spice_ignore=0}
C {lab_wire.sym} 1900 -480 0 1 {name=p5 sig_type=std_logic lab=VDD}
C {ammeter.sym} 1900 -420 0 0 {name=v_i_div_3 savecurrent=true spice_ignore=0}
C {ammeter.sym} 400 -810 0 0 {name=v_i_tail_total savecurrent=true spice_ignore=0}
C {ammeter.sym} 2330 -2790 1 1 {name=v_i_buf_mix_1_p savecurrent=true spice_ignore=0}
C {lab_wire.sym} 2380 -2560 0 1 {name=p7 sig_type=std_logic lab=VDD}
C {ammeter.sym} 2330 -2560 1 1 {name=v_i_buf_mix_1_m savecurrent=true spice_ignore=0}
C {lab_wire.sym} 2390 -2320 0 1 {name=p112 sig_type=std_logic lab=VDD}
C {ammeter.sym} 2340 -2320 1 1 {name=v_i_buf_mix_2_p savecurrent=true spice_ignore=0}
C {lab_wire.sym} 2380 -2060 0 1 {name=p151 sig_type=std_logic lab=VDD}
C {ammeter.sym} 2330 -2060 1 1 {name=v_i_buf_mix_2_m savecurrent=true spice_ignore=0}
C {lab_wire.sym} 3130 -2030 0 1 {name=p152 sig_type=std_logic lab=VDD}
C {ammeter.sym} 3080 -2030 1 1 {name=v_i_buf_mix_3_p savecurrent=true spice_ignore=0}
C {lab_wire.sym} 3130 -1760 0 1 {name=p153 sig_type=std_logic lab=VDD}
C {ammeter.sym} 3080 -1760 1 1 {name=v_i_buf_mix_3_m savecurrent=true spice_ignore=0}
C {lab_wire.sym} 3130 -1530 0 1 {name=p154 sig_type=std_logic lab=VDD}
C {ammeter.sym} 3080 -1530 1 1 {name=v_i_buf_mix_4_p savecurrent=true spice_ignore=0}
C {lab_wire.sym} 3130 -1280 0 1 {name=p155 sig_type=std_logic lab=VDD}
C {ammeter.sym} 3080 -1280 1 1 {name=v_i_buf_mix_4_m savecurrent=true spice_ignore=0}
C {ammeter.sym} 540 -670 0 0 {name=v_i_decoder savecurrent=true spice_ignore=0}
C {digital/schematic/transmission_gate.sym} 2070 -2700 0 0 {name=x26}
C {digital/schematic/transmission_gate.sym} 2070 -2490 0 0 {name=x27}
C {digital/schematic/transmission_gate.sym} 2070 -2250 0 0 {name=x28}
C {digital/schematic/transmission_gate.sym} 2070 -1990 0 0 {name=x29}
C {lab_wire.sym} 2000 -2080 0 0 {name=p60 sig_type=std_logic lab=VDD}
C {lab_wire.sym} 2000 -1900 0 0 {name=p100 sig_type=std_logic lab=VSS}
C {lab_wire.sym} 1990 -2330 0 0 {name=p102 sig_type=std_logic lab=VDD}
C {lab_wire.sym} 1990 -2160 0 0 {name=p104 sig_type=std_logic lab=VSS}
C {lab_wire.sym} 2000 -2580 0 0 {name=p106 sig_type=std_logic lab=VDD}
C {lab_wire.sym} 1990 -2400 0 0 {name=p109 sig_type=std_logic lab=VSS}
C {lab_wire.sym} 2010 -2790 0 0 {name=p156 sig_type=std_logic lab=VDD}
C {lab_wire.sym} 2000 -2610 0 0 {name=p157 sig_type=std_logic lab=VSS}
C {lab_wire.sym} 2050 -2790 0 1 {name=p158 sig_type=std_logic lab=EN_mix_div_1}
C {lab_wire.sym} 2050 -2330 0 1 {name=p159 sig_type=std_logic lab=EN_mix_2}
C {lab_wire.sym} 2050 -2080 0 1 {name=p160 sig_type=std_logic lab=EN_mix_2}
C {lab_wire.sym} 2060 -2580 0 1 {name=p161 sig_type=std_logic lab=EN_mix_div_1}
C {digital/schematic/transmission_gate.sym} 2690 -1950 0 0 {name=x30}
C {digital/schematic/transmission_gate.sym} 2690 -1680 0 0 {name=x31}
C {digital/schematic/transmission_gate.sym} 2690 -1450 0 0 {name=x32}
C {digital/schematic/transmission_gate.sym} 2690 -1200 0 0 {name=x33}
C {lab_wire.sym} 2610 -1350 0 0 {name=p162 sig_type=std_logic lab=VSS}
C {lab_wire.sym} 2620 -1100 0 0 {name=p163 sig_type=std_logic lab=VSS}
C {lab_wire.sym} 2620 -1580 0 0 {name=p164 sig_type=std_logic lab=VSS}
C {lab_wire.sym} 2610 -1850 0 0 {name=p165 sig_type=std_logic lab=VSS}
C {lab_wire.sym} 2620 -2050 0 0 {name=p166 sig_type=std_logic lab=VDD}
C {lab_wire.sym} 2610 -1790 0 0 {name=p167 sig_type=std_logic lab=VDD}
C {lab_wire.sym} 2630 -1540 0 0 {name=p168 sig_type=std_logic lab=VDD}
C {lab_wire.sym} 2620 -1300 0 0 {name=p169 sig_type=std_logic lab=VDD}
C {lab_wire.sym} 2700 -2050 0 1 {name=p170 sig_type=std_logic lab=EN_mix_3}
C {lab_wire.sym} 2700 -1790 0 1 {name=p171 sig_type=std_logic lab=EN_mix_3}
C {lab_wire.sym} 2690 -1540 0 1 {name=p172 sig_type=std_logic lab=EN_mix_4}
C {lab_wire.sym} 2690 -1300 0 1 {name=p173 sig_type=std_logic lab=EN_mix_4}
C {capa.sym} 1960 -1630 3 0 {name=C1
m=1
value=5p
footprint=1206
device="ceramic capacitor"}
C {capa.sym} 1960 -1580 3 0 {name=C2
m=1
value=5p
footprint=1206
device="ceramic capacitor"}
C {vsource.sym} 1990 -1480 0 0 {name=V1 value=1.3 savecurrent=false}
C {vsource.sym} 1990 -1000 0 0 {name=V2 value=1.3 savecurrent=false}
C {capa.sym} 1960 -1240 3 0 {name=C3
m=1
value=5p
footprint=1206
device="ceramic capacitor"}
C {capa.sym} 1960 -1200 3 0 {name=C4
m=1
value=5p
footprint=1206
device="ceramic capacitor"}
C {lab_wire.sym} 2000 -1450 0 1 {name=p174 sig_type=std_logic lab=VSS}
C {lab_wire.sym} 2000 -970 0 1 {name=p175 sig_type=std_logic lab=VSS}
C {res.sym} 1990 -1550 0 0 {name=R1
value=10k
footprint=1206
device=resistor
m=1}
C {res.sym} 2020 -1560 0 0 {name=R2
value=10k
footprint=1206
device=resistor
m=1}
C {res.sym} 1990 -1110 0 0 {name=R3
value=10k
footprint=1206
device=resistor
m=1}
C {res.sym} 2020 -1120 0 0 {name=R4
value=10k
footprint=1206
device=resistor
m=1}
C {lab_wire.sym} 2070 -1610 0 0 {name=p176 sig_type=std_logic lab=mix_1_IF_m_biased
}
C {lab_wire.sym} 2070 -1630 0 0 {name=p177 sig_type=std_logic lab=mix_1_IF_p_biased
}
C {lab_wire.sym} 2080 -1210 0 0 {name=p178 sig_type=std_logic lab=mix_2_IF_m_biased}
C {lab_wire.sym} 2080 -1190 0 0 {name=p179 sig_type=std_logic lab=mix_2_IF_p_biased}
C {divider/schematic/divider_with_tail.sym} 1230 -650 0 0 {name=x7}
C {divider/schematic/divider_with_tail.sym} 1900 -280 0 0 {name=x8}
C {divider/schematic/divider_with_tail.sym} 1900 -720 0 0 {name=x9}
C {lab_wire.sym} 340 -980 0 0 {name=p52 sig_type=std_logic lab=EN_div_2}
C {lab_wire.sym} 340 -960 0 0 {name=p53 sig_type=std_logic lab=EN_div_3}
C {lab_wire.sym} 1070 -640 0 0 {name=p182 sig_type=std_logic lab=i_div_1_100u}
C {lab_wire.sym} 1740 -710 0 0 {name=p183 sig_type=std_logic lab=i_div_2_100u}
C {lab_wire.sym} 1730 -270 0 0 {name=p184 sig_type=std_logic lab=i_div_3_100u}
C {lab_wire.sym} 1220 -1210 0 1 {name=p54 sig_type=std_logic lab=i_div_1_100u}
C {lab_wire.sym} 1280 -1190 0 1 {name=p180 sig_type=std_logic lab=i_div_2_100u}
C {lab_wire.sym} 1340 -1170 0 1 {name=p181 sig_type=std_logic lab=i_div_3_100u}
C {lab_wire.sym} 2080 -1230 0 0 {name=p132 sig_type=std_logic lab=mix_3_4_LO_Q_p}
C {lab_wire.sym} 2080 -1250 0 0 {name=p133 sig_type=std_logic lab=mix_3_4_LO_Q_m}
C {lab_wire.sym} 1700 -730 0 0 {name=p185 sig_type=std_logic lab=VSS}
C {digital/schematic/AND_gate.sym} 2270 -930 0 0 {name=x10}
C {digital/schematic/AND_gate.sym} 2570 -930 0 0 {name=x11}
C {digital/schematic/AND_gate.sym} 2950 -930 0 0 {name=x12}
C {digital/schematic/AND_gate.sym} 3260 -930 0 0 {name=x13}
C {ammeter.sym} 2820 -1060 0 1 {name=v_i_and_gates savecurrent=true spice_ignore=0}
